# Invented units: 1um site, 2um row, 1000 DBU/um.
VERSION 5.8 ;
BUSBITCHARS "[]" ;
DIVIDERCHAR "/" ;
UNITS
 DATABASE MICRONS 1000 ;
END UNITS
MANUFACTURINGGRID 0.001 ;
SITE unit
 CLASS CORE ;
 SIZE 1 BY 2 ;
 SYMMETRY Y ;
END unit
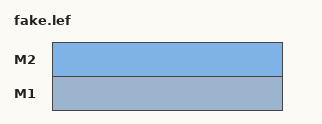
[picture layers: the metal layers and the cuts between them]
LAYER M1
 TYPE ROUTING ; DIRECTION HORIZONTAL ; PITCH 1 ; OFFSET 0 ; WIDTH 0.2 ; SPACING 0.2 ;
 RESISTANCE RPERSQ 0.01 ; CAPACITANCE CPERSQDIST 0.0001 ; EDGECAPACITANCE 0.00001 ;
END M1
LAYER M2
 TYPE ROUTING ; DIRECTION VERTICAL ; PITCH 1 ; OFFSET 0 ; WIDTH 0.2 ; SPACING 0.2 ;
 RESISTANCE RPERSQ 0.01 ; CAPACITANCE CPERSQDIST 0.0001 ; EDGECAPACITANCE 0.00001 ;
END M2

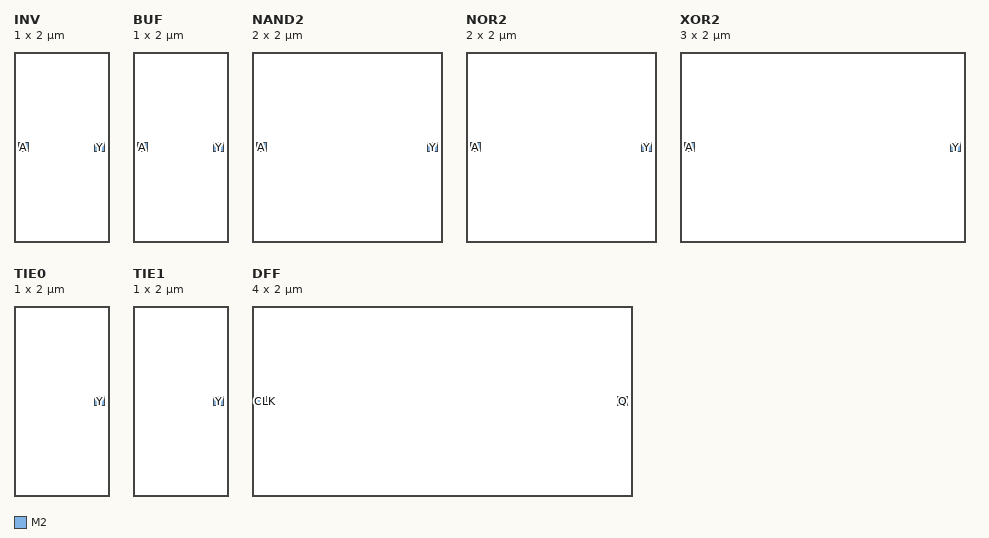
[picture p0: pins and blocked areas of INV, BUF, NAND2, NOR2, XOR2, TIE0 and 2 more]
MACRO INV
 CLASS CORE ;
 ORIGIN 0 0 ;
 SIZE 1 BY 2 ;
 SYMMETRY X Y ;
 SITE unit ;
 PIN A
  DIRECTION INPUT ;
  USE SIGNAL ;
  PORT
   LAYER M2 ;
   RECT 0.050 0.950 0.150 1.050 ;
  END
 END A
 PIN Y
  DIRECTION OUTPUT ;
  USE SIGNAL ;
  PORT
   LAYER M2 ;
   RECT 0.850 0.950 0.950 1.050 ;
  END
 END Y
END INV

MACRO BUF
 CLASS CORE ;
 ORIGIN 0 0 ;
 SIZE 1 BY 2 ;
 SYMMETRY X Y ;
 SITE unit ;
 PIN A
  DIRECTION INPUT ;
  USE SIGNAL ;
  PORT
   LAYER M2 ;
   RECT 0.050 0.950 0.150 1.050 ;
  END
 END A
 PIN Y
  DIRECTION OUTPUT ;
  USE SIGNAL ;
  PORT
   LAYER M2 ;
   RECT 0.850 0.950 0.950 1.050 ;
  END
 END Y
END BUF

MACRO NAND2
 CLASS CORE ;
 ORIGIN 0 0 ;
 SIZE 2 BY 2 ;
 SYMMETRY X Y ;
 SITE unit ;
 PIN A
  DIRECTION INPUT ;
  USE SIGNAL ;
  PORT
   LAYER M2 ;
   RECT 0.050 0.950 0.150 1.050 ;
  END
 END A
 PIN B
  DIRECTION INPUT ;
  USE SIGNAL ;
  PORT
   LAYER M2 ;
   RECT 0.050 0.950 0.150 1.050 ;
  END
 END B
 PIN Y
  DIRECTION OUTPUT ;
  USE SIGNAL ;
  PORT
   LAYER M2 ;
   RECT 1.850 0.950 1.950 1.050 ;
  END
 END Y
END NAND2

MACRO NOR2
 CLASS CORE ;
 ORIGIN 0 0 ;
 SIZE 2 BY 2 ;
 SYMMETRY X Y ;
 SITE unit ;
 PIN A
  DIRECTION INPUT ;
  USE SIGNAL ;
  PORT
   LAYER M2 ;
   RECT 0.050 0.950 0.150 1.050 ;
  END
 END A
 PIN B
  DIRECTION INPUT ;
  USE SIGNAL ;
  PORT
   LAYER M2 ;
   RECT 0.050 0.950 0.150 1.050 ;
  END
 END B
 PIN Y
  DIRECTION OUTPUT ;
  USE SIGNAL ;
  PORT
   LAYER M2 ;
   RECT 1.850 0.950 1.950 1.050 ;
  END
 END Y
END NOR2

MACRO XOR2
 CLASS CORE ;
 ORIGIN 0 0 ;
 SIZE 3 BY 2 ;
 SYMMETRY X Y ;
 SITE unit ;
 PIN A
  DIRECTION INPUT ;
  USE SIGNAL ;
  PORT
   LAYER M2 ;
   RECT 0.050 0.950 0.150 1.050 ;
  END
 END A
 PIN B
  DIRECTION INPUT ;
  USE SIGNAL ;
  PORT
   LAYER M2 ;
   RECT 0.050 0.950 0.150 1.050 ;
  END
 END B
 PIN Y
  DIRECTION OUTPUT ;
  USE SIGNAL ;
  PORT
   LAYER M2 ;
   RECT 2.850 0.950 2.950 1.050 ;
  END
 END Y
END XOR2

MACRO TIE0
 CLASS CORE ;
 ORIGIN 0 0 ;
 SIZE 1 BY 2 ;
 SYMMETRY X Y ;
 SITE unit ;
 PIN Y
  DIRECTION OUTPUT ;
  USE SIGNAL ;
  PORT
   LAYER M2 ;
   RECT 0.850 0.950 0.950 1.050 ;
  END
 END Y
END TIE0

MACRO TIE1
 CLASS CORE ;
 ORIGIN 0 0 ;
 SIZE 1 BY 2 ;
 SYMMETRY X Y ;
 SITE unit ;
 PIN Y
  DIRECTION OUTPUT ;
  USE SIGNAL ;
  PORT
   LAYER M2 ;
   RECT 0.850 0.950 0.950 1.050 ;
  END
 END Y
END TIE1

MACRO DFF
 CLASS CORE ;
 ORIGIN 0 0 ;
 SIZE 4 BY 2 ;
 SYMMETRY X Y ;
 SITE unit ;
 PIN D
  DIRECTION INPUT ;
  USE SIGNAL ;
  PORT
   LAYER M2 ;
   RECT 0.050 0.950 0.150 1.050 ;
  END
 END D
 PIN CLK
  DIRECTION INPUT ;
  USE SIGNAL ;
  PORT
   LAYER M2 ;
   RECT 0.050 0.950 0.150 1.050 ;
  END
 END CLK
 PIN Q
  DIRECTION OUTPUT ;
  USE SIGNAL ;
  PORT
   LAYER M2 ;
   RECT 3.850 0.950 3.950 1.050 ;
  END
 END Q
END DFF

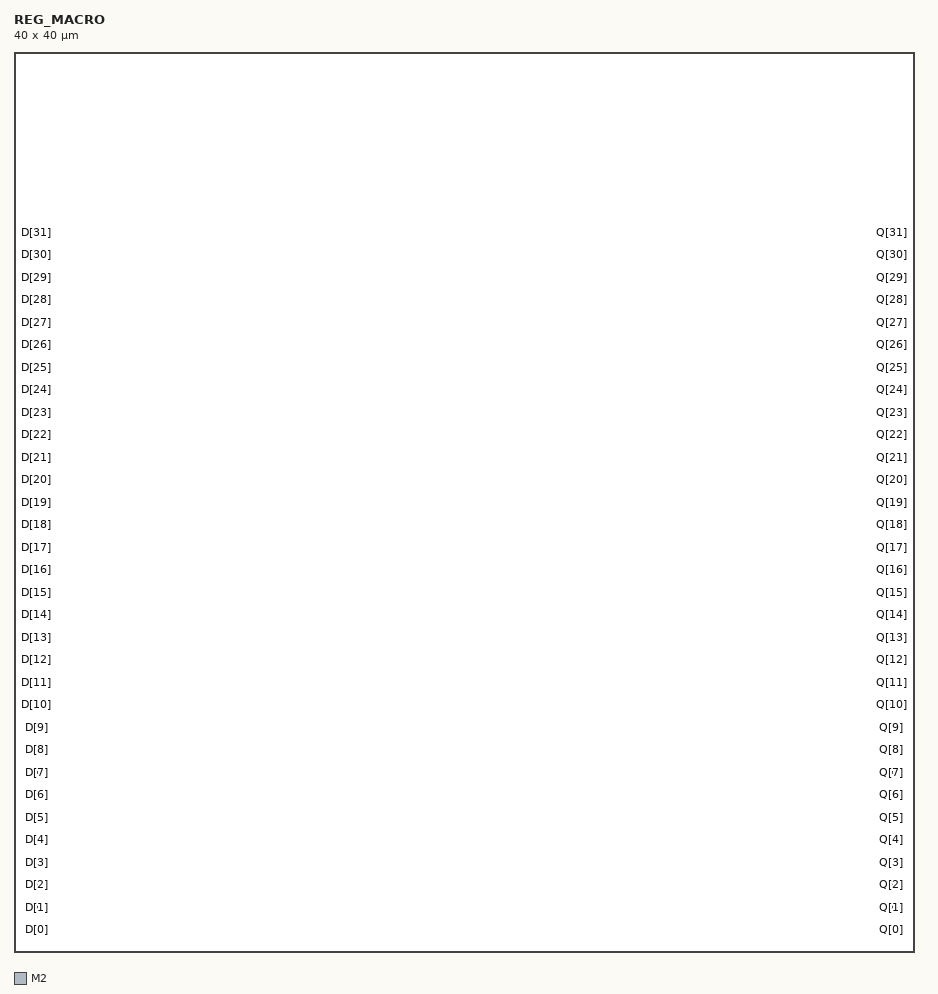
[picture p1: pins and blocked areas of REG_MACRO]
MACRO REG_MACRO
 CLASS BLOCK ;
 ORIGIN 0 0 ;
 SIZE 40 BY 40 ;
 SYMMETRY X Y ;
 PIN D[0]
  DIRECTION INPUT ;
  USE SIGNAL ;
  PORT
   LAYER M2 ;
   RECT 0.950 0.950 1.050 1.050 ;
  END
 END D[0]
 PIN Q[0]
  DIRECTION OUTPUT ;
  USE SIGNAL ;
  PORT
   LAYER M2 ;
   RECT 38.950 0.950 39.050 1.050 ;
  END
 END Q[0]
 PIN D[1]
  DIRECTION INPUT ;
  USE SIGNAL ;
  PORT
   LAYER M2 ;
   RECT 0.950 1.950 1.050 2.050 ;
  END
 END D[1]
 PIN Q[1]
  DIRECTION OUTPUT ;
  USE SIGNAL ;
  PORT
   LAYER M2 ;
   RECT 38.950 1.950 39.050 2.050 ;
  END
 END Q[1]
 PIN D[2]
  DIRECTION INPUT ;
  USE SIGNAL ;
  PORT
   LAYER M2 ;
   RECT 0.950 2.950 1.050 3.050 ;
  END
 END D[2]
 PIN Q[2]
  DIRECTION OUTPUT ;
  USE SIGNAL ;
  PORT
   LAYER M2 ;
   RECT 38.950 2.950 39.050 3.050 ;
  END
 END Q[2]
 PIN D[3]
  DIRECTION INPUT ;
  USE SIGNAL ;
  PORT
   LAYER M2 ;
   RECT 0.950 3.950 1.050 4.050 ;
  END
 END D[3]
 PIN Q[3]
  DIRECTION OUTPUT ;
  USE SIGNAL ;
  PORT
   LAYER M2 ;
   RECT 38.950 3.950 39.050 4.050 ;
  END
 END Q[3]
 PIN D[4]
  DIRECTION INPUT ;
  USE SIGNAL ;
  PORT
   LAYER M2 ;
   RECT 0.950 4.950 1.050 5.050 ;
  END
 END D[4]
 PIN Q[4]
  DIRECTION OUTPUT ;
  USE SIGNAL ;
  PORT
   LAYER M2 ;
   RECT 38.950 4.950 39.050 5.050 ;
  END
 END Q[4]
 PIN D[5]
  DIRECTION INPUT ;
  USE SIGNAL ;
  PORT
   LAYER M2 ;
   RECT 0.950 5.950 1.050 6.050 ;
  END
 END D[5]
 PIN Q[5]
  DIRECTION OUTPUT ;
  USE SIGNAL ;
  PORT
   LAYER M2 ;
   RECT 38.950 5.950 39.050 6.050 ;
  END
 END Q[5]
 PIN D[6]
  DIRECTION INPUT ;
  USE SIGNAL ;
  PORT
   LAYER M2 ;
   RECT 0.950 6.950 1.050 7.050 ;
  END
 END D[6]
 PIN Q[6]
  DIRECTION OUTPUT ;
  USE SIGNAL ;
  PORT
   LAYER M2 ;
   RECT 38.950 6.950 39.050 7.050 ;
  END
 END Q[6]
 PIN D[7]
  DIRECTION INPUT ;
  USE SIGNAL ;
  PORT
   LAYER M2 ;
   RECT 0.950 7.950 1.050 8.050 ;
  END
 END D[7]
 PIN Q[7]
  DIRECTION OUTPUT ;
  USE SIGNAL ;
  PORT
   LAYER M2 ;
   RECT 38.950 7.950 39.050 8.050 ;
  END
 END Q[7]
 PIN D[8]
  DIRECTION INPUT ;
  USE SIGNAL ;
  PORT
   LAYER M2 ;
   RECT 0.950 8.950 1.050 9.050 ;
  END
 END D[8]
 PIN Q[8]
  DIRECTION OUTPUT ;
  USE SIGNAL ;
  PORT
   LAYER M2 ;
   RECT 38.950 8.950 39.050 9.050 ;
  END
 END Q[8]
 PIN D[9]
  DIRECTION INPUT ;
  USE SIGNAL ;
  PORT
   LAYER M2 ;
   RECT 0.950 9.950 1.050 10.050 ;
  END
 END D[9]
 PIN Q[9]
  DIRECTION OUTPUT ;
  USE SIGNAL ;
  PORT
   LAYER M2 ;
   RECT 38.950 9.950 39.050 10.050 ;
  END
 END Q[9]
 PIN D[10]
  DIRECTION INPUT ;
  USE SIGNAL ;
  PORT
   LAYER M2 ;
   RECT 0.950 10.950 1.050 11.050 ;
  END
 END D[10]
 PIN Q[10]
  DIRECTION OUTPUT ;
  USE SIGNAL ;
  PORT
   LAYER M2 ;
   RECT 38.950 10.950 39.050 11.050 ;
  END
 END Q[10]
 PIN D[11]
  DIRECTION INPUT ;
  USE SIGNAL ;
  PORT
   LAYER M2 ;
   RECT 0.950 11.950 1.050 12.050 ;
  END
 END D[11]
 PIN Q[11]
  DIRECTION OUTPUT ;
  USE SIGNAL ;
  PORT
   LAYER M2 ;
   RECT 38.950 11.950 39.050 12.050 ;
  END
 END Q[11]
 PIN D[12]
  DIRECTION INPUT ;
  USE SIGNAL ;
  PORT
   LAYER M2 ;
   RECT 0.950 12.950 1.050 13.050 ;
  END
 END D[12]
 PIN Q[12]
  DIRECTION OUTPUT ;
  USE SIGNAL ;
  PORT
   LAYER M2 ;
   RECT 38.950 12.950 39.050 13.050 ;
  END
 END Q[12]
 PIN D[13]
  DIRECTION INPUT ;
  USE SIGNAL ;
  PORT
   LAYER M2 ;
   RECT 0.950 13.950 1.050 14.050 ;
  END
 END D[13]
 PIN Q[13]
  DIRECTION OUTPUT ;
  USE SIGNAL ;
  PORT
   LAYER M2 ;
   RECT 38.950 13.950 39.050 14.050 ;
  END
 END Q[13]
 PIN D[14]
  DIRECTION INPUT ;
  USE SIGNAL ;
  PORT
   LAYER M2 ;
   RECT 0.950 14.950 1.050 15.050 ;
  END
 END D[14]
 PIN Q[14]
  DIRECTION OUTPUT ;
  USE SIGNAL ;
  PORT
   LAYER M2 ;
   RECT 38.950 14.950 39.050 15.050 ;
  END
 END Q[14]
 PIN D[15]
  DIRECTION INPUT ;
  USE SIGNAL ;
  PORT
   LAYER M2 ;
   RECT 0.950 15.950 1.050 16.050 ;
  END
 END D[15]
 PIN Q[15]
  DIRECTION OUTPUT ;
  USE SIGNAL ;
  PORT
   LAYER M2 ;
   RECT 38.950 15.950 39.050 16.050 ;
  END
 END Q[15]
 PIN D[16]
  DIRECTION INPUT ;
  USE SIGNAL ;
  PORT
   LAYER M2 ;
   RECT 0.950 16.950 1.050 17.050 ;
  END
 END D[16]
 PIN Q[16]
  DIRECTION OUTPUT ;
  USE SIGNAL ;
  PORT
   LAYER M2 ;
   RECT 38.950 16.950 39.050 17.050 ;
  END
 END Q[16]
 PIN D[17]
  DIRECTION INPUT ;
  USE SIGNAL ;
  PORT
   LAYER M2 ;
   RECT 0.950 17.950 1.050 18.050 ;
  END
 END D[17]
 PIN Q[17]
  DIRECTION OUTPUT ;
  USE SIGNAL ;
  PORT
   LAYER M2 ;
   RECT 38.950 17.950 39.050 18.050 ;
  END
 END Q[17]
 PIN D[18]
  DIRECTION INPUT ;
  USE SIGNAL ;
  PORT
   LAYER M2 ;
   RECT 0.950 18.950 1.050 19.050 ;
  END
 END D[18]
 PIN Q[18]
  DIRECTION OUTPUT ;
  USE SIGNAL ;
  PORT
   LAYER M2 ;
   RECT 38.950 18.950 39.050 19.050 ;
  END
 END Q[18]
 PIN D[19]
  DIRECTION INPUT ;
  USE SIGNAL ;
  PORT
   LAYER M2 ;
   RECT 0.950 19.950 1.050 20.050 ;
  END
 END D[19]
 PIN Q[19]
  DIRECTION OUTPUT ;
  USE SIGNAL ;
  PORT
   LAYER M2 ;
   RECT 38.950 19.950 39.050 20.050 ;
  END
 END Q[19]
 PIN D[20]
  DIRECTION INPUT ;
  USE SIGNAL ;
  PORT
   LAYER M2 ;
   RECT 0.950 20.950 1.050 21.050 ;
  END
 END D[20]
 PIN Q[20]
  DIRECTION OUTPUT ;
  USE SIGNAL ;
  PORT
   LAYER M2 ;
   RECT 38.950 20.950 39.050 21.050 ;
  END
 END Q[20]
 PIN D[21]
  DIRECTION INPUT ;
  USE SIGNAL ;
  PORT
   LAYER M2 ;
   RECT 0.950 21.950 1.050 22.050 ;
  END
 END D[21]
 PIN Q[21]
  DIRECTION OUTPUT ;
  USE SIGNAL ;
  PORT
   LAYER M2 ;
   RECT 38.950 21.950 39.050 22.050 ;
  END
 END Q[21]
 PIN D[22]
  DIRECTION INPUT ;
  USE SIGNAL ;
  PORT
   LAYER M2 ;
   RECT 0.950 22.950 1.050 23.050 ;
  END
 END D[22]
 PIN Q[22]
  DIRECTION OUTPUT ;
  USE SIGNAL ;
  PORT
   LAYER M2 ;
   RECT 38.950 22.950 39.050 23.050 ;
  END
 END Q[22]
 PIN D[23]
  DIRECTION INPUT ;
  USE SIGNAL ;
  PORT
   LAYER M2 ;
   RECT 0.950 23.950 1.050 24.050 ;
  END
 END D[23]
 PIN Q[23]
  DIRECTION OUTPUT ;
  USE SIGNAL ;
  PORT
   LAYER M2 ;
   RECT 38.950 23.950 39.050 24.050 ;
  END
 END Q[23]
 PIN D[24]
  DIRECTION INPUT ;
  USE SIGNAL ;
  PORT
   LAYER M2 ;
   RECT 0.950 24.950 1.050 25.050 ;
  END
 END D[24]
 PIN Q[24]
  DIRECTION OUTPUT ;
  USE SIGNAL ;
  PORT
   LAYER M2 ;
   RECT 38.950 24.950 39.050 25.050 ;
  END
 END Q[24]
 PIN D[25]
  DIRECTION INPUT ;
  USE SIGNAL ;
  PORT
   LAYER M2 ;
   RECT 0.950 25.950 1.050 26.050 ;
  END
 END D[25]
 PIN Q[25]
  DIRECTION OUTPUT ;
  USE SIGNAL ;
  PORT
   LAYER M2 ;
   RECT 38.950 25.950 39.050 26.050 ;
  END
 END Q[25]
 PIN D[26]
  DIRECTION INPUT ;
  USE SIGNAL ;
  PORT
   LAYER M2 ;
   RECT 0.950 26.950 1.050 27.050 ;
  END
 END D[26]
 PIN Q[26]
  DIRECTION OUTPUT ;
  USE SIGNAL ;
  PORT
   LAYER M2 ;
   RECT 38.950 26.950 39.050 27.050 ;
  END
 END Q[26]
 PIN D[27]
  DIRECTION INPUT ;
  USE SIGNAL ;
  PORT
   LAYER M2 ;
   RECT 0.950 27.950 1.050 28.050 ;
  END
 END D[27]
 PIN Q[27]
  DIRECTION OUTPUT ;
  USE SIGNAL ;
  PORT
   LAYER M2 ;
   RECT 38.950 27.950 39.050 28.050 ;
  END
 END Q[27]
 PIN D[28]
  DIRECTION INPUT ;
  USE SIGNAL ;
  PORT
   LAYER M2 ;
   RECT 0.950 28.950 1.050 29.050 ;
  END
 END D[28]
 PIN Q[28]
  DIRECTION OUTPUT ;
  USE SIGNAL ;
  PORT
   LAYER M2 ;
   RECT 38.950 28.950 39.050 29.050 ;
  END
 END Q[28]
 PIN D[29]
  DIRECTION INPUT ;
  USE SIGNAL ;
  PORT
   LAYER M2 ;
   RECT 0.950 29.950 1.050 30.050 ;
  END
 END D[29]
 PIN Q[29]
  DIRECTION OUTPUT ;
  USE SIGNAL ;
  PORT
   LAYER M2 ;
   RECT 38.950 29.950 39.050 30.050 ;
  END
 END Q[29]
 PIN D[30]
  DIRECTION INPUT ;
  USE SIGNAL ;
  PORT
   LAYER M2 ;
   RECT 0.950 30.950 1.050 31.050 ;
  END
 END D[30]
 PIN Q[30]
  DIRECTION OUTPUT ;
  USE SIGNAL ;
  PORT
   LAYER M2 ;
   RECT 38.950 30.950 39.050 31.050 ;
  END
 END Q[30]
 PIN D[31]
  DIRECTION INPUT ;
  USE SIGNAL ;
  PORT
   LAYER M2 ;
   RECT 0.950 31.950 1.050 32.050 ;
  END
 END D[31]
 PIN Q[31]
  DIRECTION OUTPUT ;
  USE SIGNAL ;
  PORT
   LAYER M2 ;
   RECT 38.950 31.950 39.050 32.050 ;
  END
 END Q[31]
END REG_MACRO

END LIBRARY
